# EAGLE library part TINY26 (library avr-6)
Atmel Tiny26/261/461/861

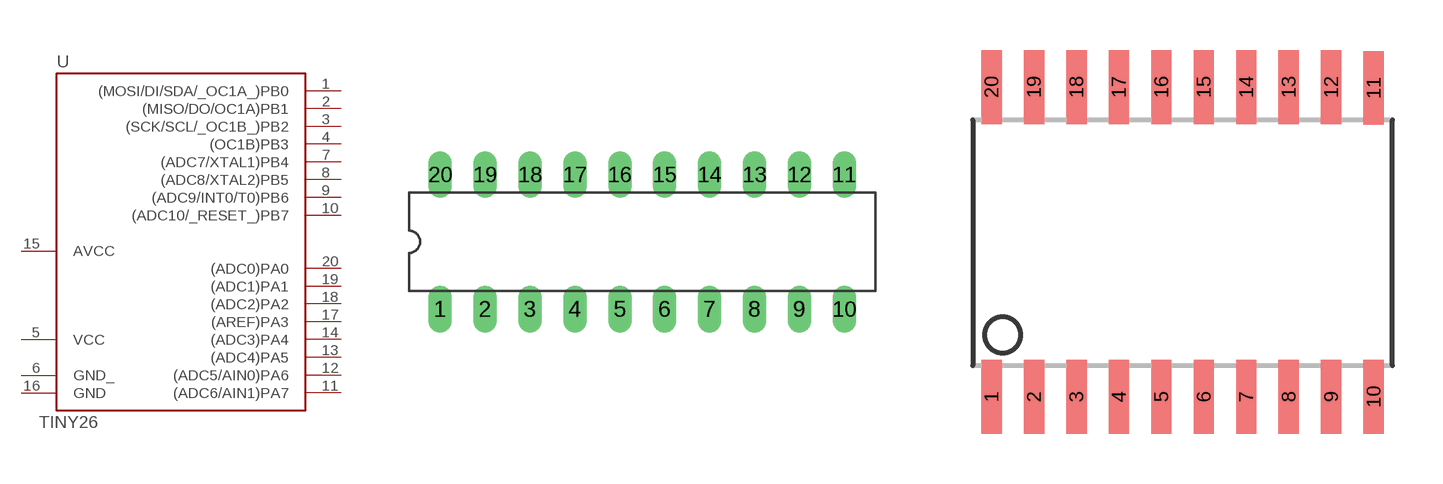
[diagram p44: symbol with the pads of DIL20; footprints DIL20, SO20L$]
Designator prefix -

## TINY26P  [DIL20]
1  (MOSI/DI/SDA/_OC1A_)PB0
2  (MISO/DO/OC1A)PB1
3  (SCK/SCL/_OC1B_)PB2
4  (OC1B)PB3
5  VCC  pwr
6  GND_  pwr
7  (ADC7/XTAL1)PB4
8  (ADC8/XTAL2)PB5
9  (ADC9/INT0/T0)PB6
10  (ADC10/_RESET_)PB7
11  (ADC6/AIN1)PA7
12  (ADC5/AIN0)PA6
13  (ADC4)PA5
14  (ADC3)PA4
15  AVCC  pwr
16  GND  pwr
17  (AREF)PA3
18  (ADC2)PA2
19  (ADC1)PA1
20  (ADC0)PA0

## TINY26S  [SO20L$]
Pads as for DIL20

## TINY26M  [MLF32]
2  (OC1B)PB3
4  VCC  pwr
5  GND_  pwr
7  (ADC7/XTAL1)PB4
8  (ADC8/XTAL2)PB5
10  (ADC9/INT0/T0)PB6
11  (ADC10/_RESET_)PB7
13  (ADC6/AIN1)PA7
14  (ADC5/AIN0)PA6
15  (ADC4)PA5
17  (ADC3)PA4
18  AVCC  pwr
21  GND  pwr
22  (AREF)PA3
23  (ADC2)PA2
25  (ADC1)PA1
26  (ADC0)PA0
30  (MOSI/DI/SDA/_OC1A_)PB0
31  (MISO/DO/OC1A)PB1
32  (SCK/SCL/_OC1B_)PB2

## Footprint DIL20 (pad centres in mm)
Dual In Line
drill 0.813 long: 1 -11.43,-3.81; 2 -8.89,-3.81; 3 -6.35,-3.81; 4 -3.81,-3.81; 5 -1.27,-3.81; 6 1.27,-3.81; 7 3.81,-3.81; 8 6.35,-3.81; 9 8.89,-3.81; 10 11.43,-3.81; 11 11.43,3.81; 12 8.89,3.81; 13 6.35,3.81; 14 3.81,3.81; 15 1.27,3.81; 16 -1.27,3.81; 17 -3.81,3.81; 18 -6.35,3.81; 19 -8.89,3.81; 20 -11.43,3.81

## Footprint SO20L$ (pad centres in mm)
Small Outline Package, large
smd 0.61 x 2.21: 1 -5.715,-4.636; 2 -4.445,-4.636; 3 -3.175,-4.636; 4 -1.905,-4.636; 5 -0.635,-4.636; 6 0.635,-4.636; 7 1.905,-4.636; 8 3.175,-4.636; 9 4.445,-4.636; 10 5.715,-4.636; 11 5.715,4.61; 12 4.445,4.636; 13 3.175,4.636; 14 1.905,4.636; 15 0.635,4.636; 16 -0.635,4.636; 17 -1.905,4.636; 18 -3.175,4.636; 19 -4.445,4.636; 20 -5.715,4.636

## Footprint MLF32 (pad centres in mm)
32M1-A Micro Lead Frame package (MLF)
smd 0.7 x 0.3: 1 -2.35,1.75; 2 -2.35,1.25; 3 -2.35,0.75; 4 -2.35,0.25; 5 -2.35,-0.25; 6 -2.35,-0.75; 7 -2.35,-1.25; 8 -2.35,-1.75; 17 2.35,-1.75; 18 2.35,-1.25; 19 2.35,-0.75; 20 2.35,-0.25; 21 2.35,0.25; 22 2.35,0.75; 23 2.35,1.25; 24 2.35,1.75
smd 0.3 x 0.7: 9 -1.75,-2.35; 10 -1.25,-2.35; 11 -0.75,-2.35; 12 -0.25,-2.35; 13 0.25,-2.35; 14 0.75,-2.35; 15 1.25,-2.35; 16 1.75,-2.35; 25 1.75,2.35; 26 1.25,2.35; 27 0.75,2.35; 28 0.25,2.35; 29 -0.25,2.35; 30 -0.75,2.35; 31 -1.25,2.35; 32 -1.75,2.35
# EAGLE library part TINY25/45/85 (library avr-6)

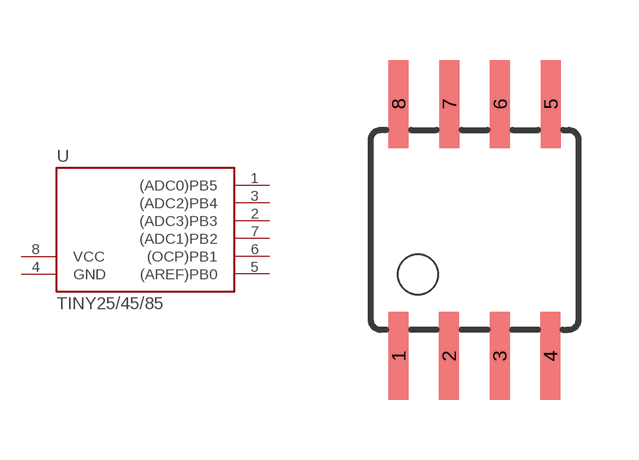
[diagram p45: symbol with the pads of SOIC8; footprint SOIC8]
Designator prefix -

## TINY25/45/85-20SU  [SOIC8]
1  (ADC0)PB5
2  (ADC3)PB3
3  (ADC2)PB4
4  GND  pwr
5  (AREF)PB0
6  (OCP)PB1
7  (ADC1)PB2
8  VCC  pwr

## Footprint SOIC8 (pad centres in mm)
Wide Plastic Gull Wing Small Outline Package
smd 0.5 x 2.2: 1 -1.905,-3.154; 2 -0.645,-3.154; 3 0.625,-3.154; 4 1.895,-3.154; 5 1.905,3.154; 6 0.635,3.154; 7 -0.635,3.154; 8 -1.905,3.154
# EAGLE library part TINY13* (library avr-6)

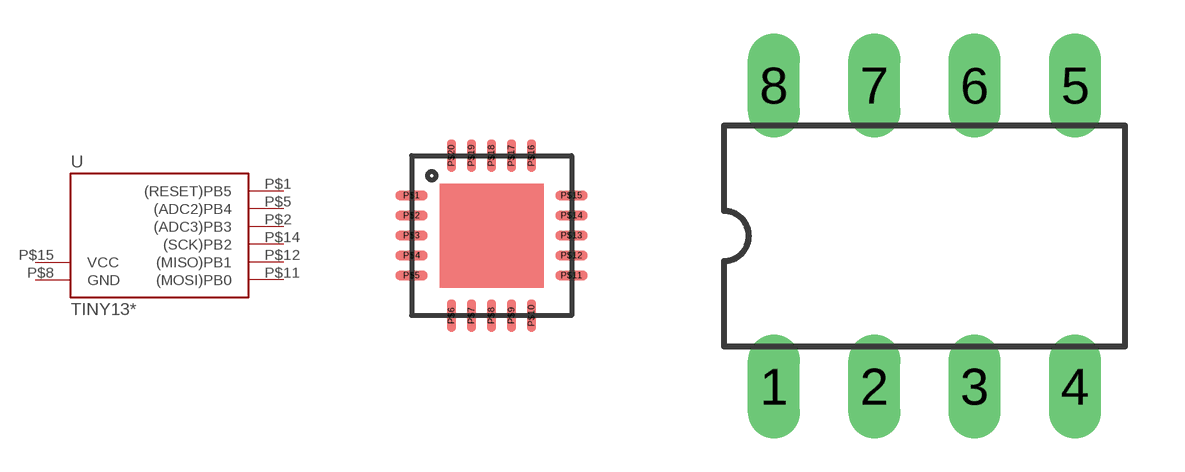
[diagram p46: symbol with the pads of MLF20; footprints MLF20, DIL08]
Designator prefix -

## TINY1320M1  [MLF20]
P$1  (RESET)PB5
P$2  (ADC3)PB3
P$5  (ADC2)PB4
P$8  GND  pwr
P$11  (MOSI)PB0
P$12  (MISO)PB1
P$14  (SCK)PB2
P$15  VCC  pwr

## TINY138P3  [DIL08]
1  (RESET)PB5
2  (ADC3)PB3
3  (ADC2)PB4
4  GND  pwr
5  (MOSI)PB0
6  (MISO)PB1
7  (SCK)PB2
8  VCC  pwr

## TINY138S2  [SO08]
Pads as for DIL08

## TINY13S8S1  [SO08-GW]
Pads as for DIL08

## Footprint MLF20 (pad centres in mm)
HP-VFQFP-N20 Micro Lead Frame package (MLF)
smd 0.8 x 0.23: P$1 -2,1; P$2 -2,0.5; P$3 -2,0; P$4 -2,-0.5; P$5 -2,-1; P$11 2,-1; P$12 2,-0.5; P$13 2,0; P$14 2,0.5; P$15 2,1
smd 0.23 x 0.8: P$6 -1,-2; P$7 -0.5,-2; P$8 0,-2; P$9 0.5,-2; P$10 1,-2; P$16 1,2; P$17 0.5,2; P$18 0,2; P$19 -0.5,2; P$20 -1,2

## Footprint DIL08 (pad centres in mm)
Dual In Line
drill 0.813 long: 1 -3.81,-3.81; 2 -1.27,-3.81; 3 1.27,-3.81; 4 3.81,-3.81; 5 3.81,3.81; 6 1.27,3.81; 7 -1.27,3.81; 8 -3.81,3.81

## Footprint SO08 (pad centres in mm)
Small Outline Package
smd 0.61 x 2.21: 1 -1.905,-2.616; 2 -0.635,-2.616; 3 0.635,-2.616; 4 1.905,-2.616; 5 1.905,2.616; 6 0.635,2.616; 7 -0.635,2.616; 8 -1.905,2.616

## Footprint SO08-GW (pad centres in mm)
Small Outline Package, gull wing
smd 0.762 x 2.21: 1 -3.81,-4.318; 2 -1.27,-4.318; 3 1.27,-4.318; 4 3.81,-4.318; 5 3.81,4.318; 6 1.27,4.318; 7 -1.27,4.318; 8 -3.81,4.318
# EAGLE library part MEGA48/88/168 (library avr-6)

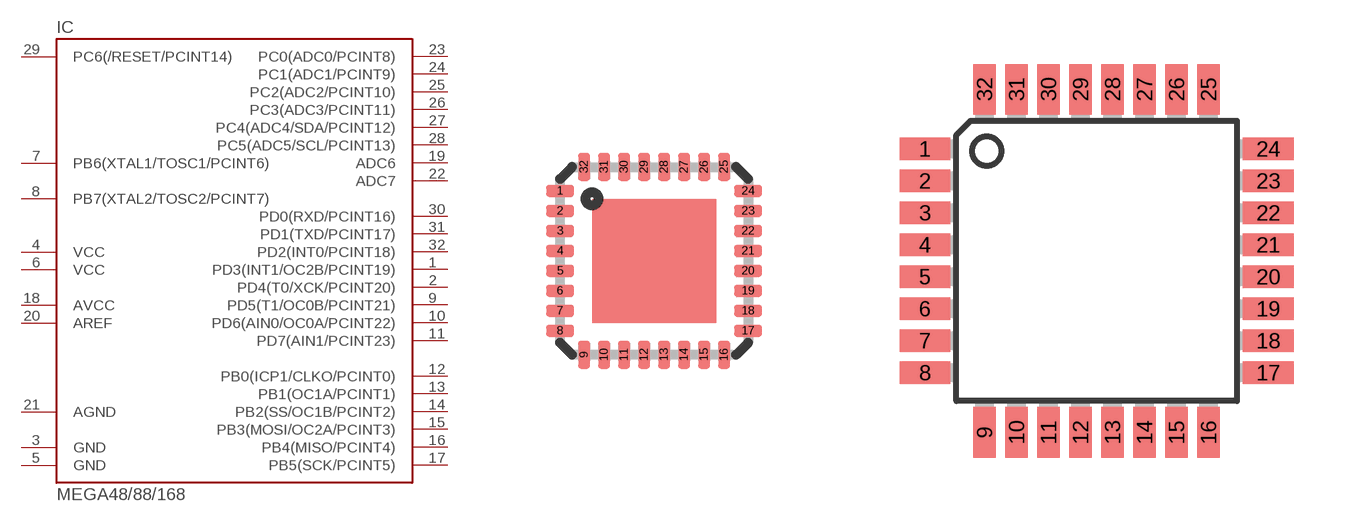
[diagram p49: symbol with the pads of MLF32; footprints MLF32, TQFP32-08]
Designator prefix IC

## MEGA48/88/168-MU  [MLF32]
1  PD3(INT1/OC2B/PCINT19)
2  PD4(T0/XCK/PCINT20)
3  GND  pwr
4  VCC  pwr
5  GND  pwr
6  VCC  pwr
7  PB6(XTAL1/TOSC1/PCINT6)
8  PB7(XTAL2/TOSC2/PCINT7)
9  PD5(T1/OC0B/PCINT21)
10  PD6(AIN0/OC0A/PCINT22)
11  PD7(AIN1/PCINT23)
12  PB0(ICP1/CLKO/PCINT0)
13  PB1(OC1A/PCINT1)
14  PB2(SS/OC1B/PCINT2)
15  PB3(MOSI/OC2A/PCINT3)
16  PB4(MISO/PCINT4)
17  PB5(SCK/PCINT5)
18  AVCC  pas
19  ADC6  pas
20  AREF  pas
21  AGND  pwr
22  ADC7  pas
23  PC0(ADC0/PCINT8)
24  PC1(ADC1/PCINT9)
25  PC2(ADC2/PCINT10)
26  PC3(ADC3/PCINT11)
27  PC4(ADC4/SDA/PCINT12)
28  PC5(ADC5/SCL/PCINT13)
29  PC6(/RESET/PCINT14)
30  PD0(RXD/PCINT16)
31  PD1(TXD/PCINT17)
32  PD2(INT0/PCINT18)

## MEGA48/88/168-AU  [TQFP32-08]
Pads as for MLF32

## Footprint MLF32 (pad centres in mm)
32M1-A Micro Lead Frame package (MLF)
smd 0.7 x 0.3: 1 -2.35,1.75; 2 -2.35,1.25; 3 -2.35,0.75; 4 -2.35,0.25; 5 -2.35,-0.25; 6 -2.35,-0.75; 7 -2.35,-1.25; 8 -2.35,-1.75; 17 2.35,-1.75; 18 2.35,-1.25; 19 2.35,-0.75; 20 2.35,-0.25; 21 2.35,0.25; 22 2.35,0.75; 23 2.35,1.25; 24 2.35,1.75
smd 0.3 x 0.7: 9 -1.75,-2.35; 10 -1.25,-2.35; 11 -0.75,-2.35; 12 -0.25,-2.35; 13 0.25,-2.35; 14 0.75,-2.35; 15 1.25,-2.35; 16 1.75,-2.35; 25 1.75,2.35; 26 1.25,2.35; 27 0.75,2.35; 28 0.25,2.35; 29 -0.25,2.35; 30 -0.75,2.35; 31 -1.25,2.35; 32 -1.75,2.35

## Footprint TQFP32-08 (pad centres in mm)
Thin Plasic Quad Flat Package Grid 0.8 mm
smd 1.27 x 0.559: 1 -4.293,2.8; 2 -4.293,2; 3 -4.293,1.2; 4 -4.293,0.4; 5 -4.293,-0.4; 6 -4.293,-1.2; 7 -4.293,-2; 8 -4.293,-2.8; 17 4.293,-2.8; 18 4.293,-2; 19 4.293,-1.2; 20 4.293,-0.4; 21 4.293,0.4; 22 4.293,1.2; 23 4.293,2; 24 4.293,2.8
smd 0.559 x 1.27: 9 -2.8,-4.293; 10 -2,-4.293; 11 -1.2,-4.293; 12 -0.4,-4.293; 13 0.4,-4.293; 14 1.2,-4.293; 15 2,-4.293; 16 2.8,-4.293; 25 2.8,4.293; 26 2,4.293; 27 1.2,4.293; 28 0.4,4.293; 29 -0.4,4.293; 30 -1.2,4.293; 31 -2,4.293; 32 -2.8,4.293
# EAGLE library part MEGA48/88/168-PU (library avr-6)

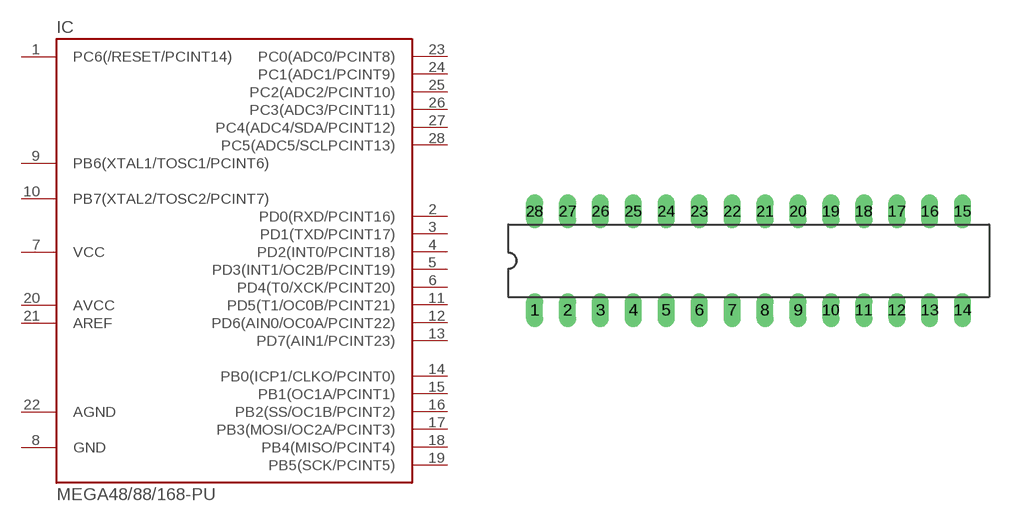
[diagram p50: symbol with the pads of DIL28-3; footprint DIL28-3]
Designator prefix IC

## MEGA48/88/168-PU  [DIL28-3]
1  PC6(/RESET/PCINT14)
2  PD0(RXD/PCINT16)
3  PD1(TXD/PCINT17)
4  PD2(INT0/PCINT18)
5  PD3(INT1/OC2B/PCINT19)
6  PD4(T0/XCK/PCINT20)
7  VCC  pwr
8  GND  pwr
9  PB6(XTAL1/TOSC1/PCINT6)
10  PB7(XTAL2/TOSC2/PCINT7)
11  PD5(T1/OC0B/PCINT21)
12  PD6(AIN0/OC0A/PCINT22)
13  PD7(AIN1/PCINT23)
14  PB0(ICP1/CLKO/PCINT0)
15  PB1(OC1A/PCINT1)
16  PB2(SS/OC1B/PCINT2)
17  PB3(MOSI/OC2A/PCINT3)
18  PB4(MISO/PCINT4)
19  PB5(SCK/PCINT5)
20  AVCC  pas
21  AREF  pas
22  AGND  pwr
23  PC0(ADC0/PCINT8)
24  PC1(ADC1/PCINT9)
25  PC2(ADC2/PCINT10)
26  PC3(ADC3/PCINT11)
27  PC4(ADC4/SDA/PCINT12)
28  PC5(ADC5/SCLPCINT13)

## Footprint DIL28-3 (pad centres in mm)
Dual In Line 0.3 inch
drill 0.813 long: 1 -16.51,-3.81; 2 -13.97,-3.81; 3 -11.43,-3.81; 4 -8.89,-3.81; 5 -6.35,-3.81; 6 -3.81,-3.81; 7 -1.27,-3.81; 8 1.27,-3.81; 9 3.81,-3.81; 10 6.35,-3.81; 11 8.89,-3.81; 12 11.43,-3.81; 13 13.97,-3.81; 14 16.51,-3.81; 15 16.51,3.81; 16 13.97,3.81; 17 11.43,3.81; 18 8.89,3.81; 19 6.35,3.81; 20 3.81,3.81; 21 1.27,3.81; 22 -1.27,3.81; 23 -3.81,3.81; 24 -6.35,3.81; 25 -8.89,3.81; 26 -11.43,3.81; 27 -13.97,3.81; 28 -16.51,3.81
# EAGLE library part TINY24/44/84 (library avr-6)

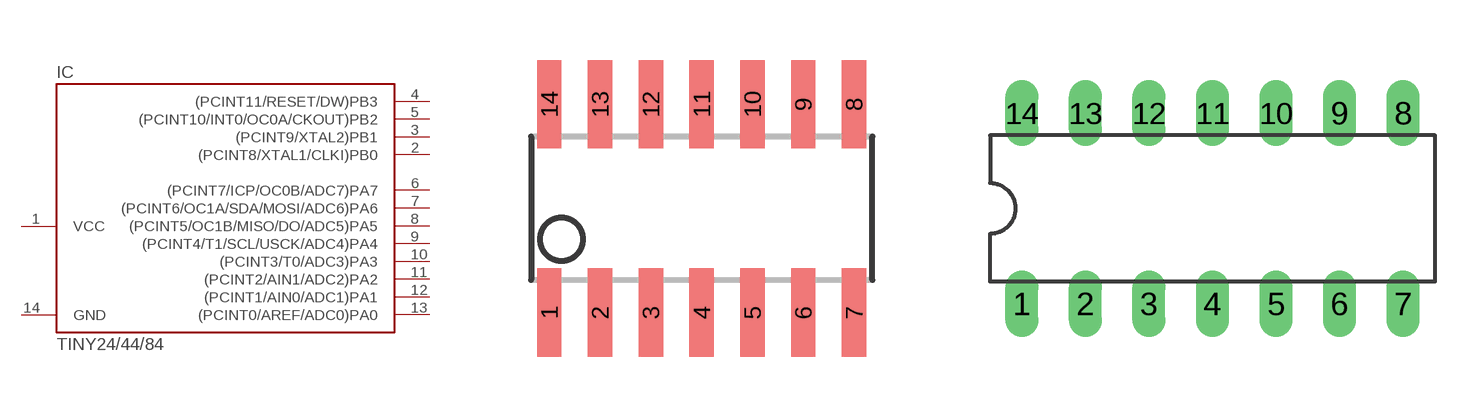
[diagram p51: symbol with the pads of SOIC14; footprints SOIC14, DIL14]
Designator prefix IC

## TINY24/44/84-SSU  [SOIC14]
1  VCC  pwr
2  (PCINT8/XTAL1/CLKI)PB0
3  (PCINT9/XTAL2)PB1
4  (PCINT11/RESET/DW)PB3
5  (PCINT10/INT0/OC0A/CKOUT)PB2
6  (PCINT7/ICP/OC0B/ADC7)PA7
7  (PCINT6/OC1A/SDA/MOSI/ADC6)PA6
8  (PCINT5/OC1B/MISO/DO/ADC5)PA5
9  (PCINT4/T1/SCL/USCK/ADC4)PA4
10  (PCINT3/T0/ADC3)PA3
11  (PCINT2/AIN1/ADC2)PA2
12  (PCINT1/AIN0/ADC1)PA1
13  (PCINT0/AREF/ADC0)PA0
14  GND  pwr

## TINY24/44/84-PU  [DIL14]
Pads as for SOIC14

## TINY24/44/84-MU  [QFN/MLF20]
1  (PCINT4/T1/SCL/USCK/ADC4)PA4
2  (PCINT3/T0/ADC3)PA3
3  (PCINT2/AIN1/ADC2)PA2
4  (PCINT1/AIN0/ADC1)PA1
5  (PCINT0/AREF/ADC0)PA0
8  GND  pwr
9  VCC  pwr
11  (PCINT8/XTAL1/CLKI)PB0
12  (PCINT9/XTAL2)PB1
13  (PCINT11/RESET/DW)PB3
14  (PCINT10/INT0/OC0A/CKOUT)PB2
15  (PCINT7/ICP/OC0B/ADC7)PA7
16  (PCINT6/OC1A/SDA/MOSI/ADC6)PA6
20  (PCINT5/OC1B/MISO/DO/ADC5)PA5

## Footprint SOIC14 (pad centres in mm)
Small Outline Package
smd 0.61 x 2.21: 1 -3.81,-2.603; 2 -2.54,-2.603; 3 -1.27,-2.603; 4 0,-2.603; 5 1.27,-2.603; 6 2.54,-2.603; 7 3.81,-2.603; 8 3.81,2.603; 9 2.54,2.603; 10 1.27,2.603; 11 0,2.603; 12 -1.27,2.603; 13 -2.54,2.603; 14 -3.81,2.603

## Footprint DIL14 (pad centres in mm)
Dual In Line Package
drill 0.813 long: 1 -7.62,-3.81; 2 -5.08,-3.81; 3 -2.54,-3.81; 4 0,-3.81; 5 2.54,-3.81; 6 5.08,-3.81; 7 7.62,-3.81; 8 7.62,3.81; 9 5.08,3.81; 10 2.54,3.81; 11 0,3.81; 12 -2.54,3.81; 13 -5.08,3.81; 14 -7.62,3.81

## Footprint QFN/MLF20 (pad centres in mm)
HP-VFQFP-N20 Micro Lead Frame package (MLF)
smd 0.9 x 0.35: 1 -2.25,1.3; 2 -2.25,0.65; 3 -2.25,0; 4 -2.25,-0.65; 5 -2.25,-1.3; 11 2.25,-1.3; 12 2.25,-0.65; 13 2.25,0; 14 2.25,0.65; 15 2.25,1.3
smd 0.35 x 0.9: 6 -1.3,-2.25; 7 -0.65,-2.25; 8 0,-2.25; 9 0.65,-2.25; 10 1.3,-2.25; 16 1.3,2.25; 17 0.65,2.25; 18 0,2.25; 19 -0.65,2.25; 20 -1.3,2.25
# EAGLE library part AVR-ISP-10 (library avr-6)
AVR ISP-10 Serial Programming Header

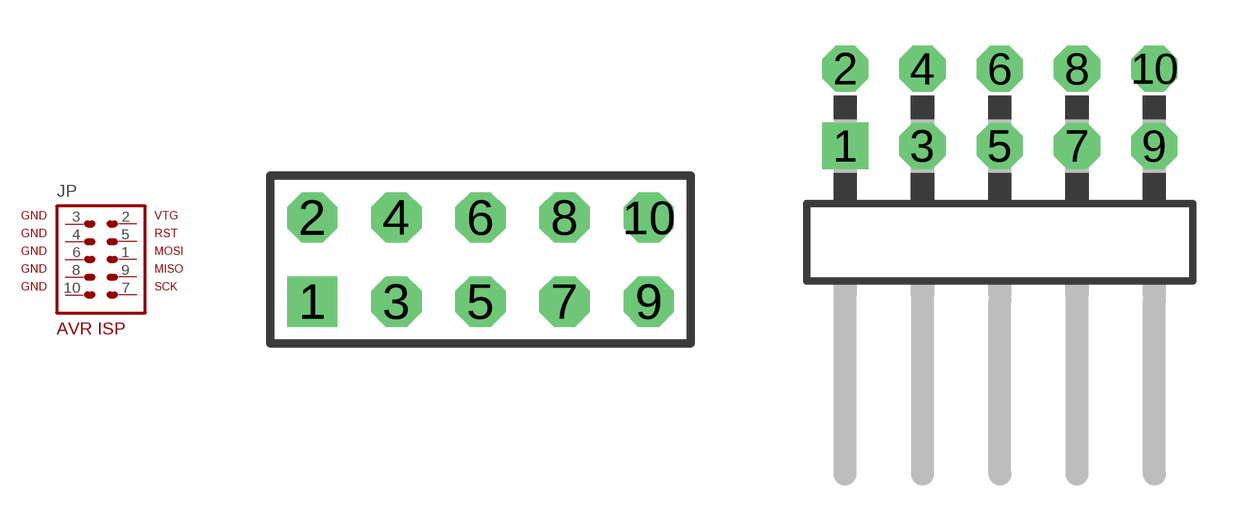
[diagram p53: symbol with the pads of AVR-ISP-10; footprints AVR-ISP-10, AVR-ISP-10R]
Designator prefix JP

## AVR-ISP-10  [AVR-ISP-10]
1  1  pas
2  2  pas
3  3  pas
4  4  pas
5  5  pas
6  6  pas
7  7  pas
8  8  pas
9  9  pas
10  10  pas

## AVR-ISP-10R  [AVR-ISP-10R]
Pads as for AVR-ISP-10

## Footprint AVR-ISP-10 (pad centres in mm)
PIN HEADER AVR ISP 10 Pin, 0.1" Straight
drill 1.016 square: 1 -5.08,-1.27
drill 1.016 octagon: 2 -5.08,1.27; 3 -2.54,-1.27; 4 -2.54,1.27; 5 0,-1.27; 6 0,1.27; 7 2.54,-1.27; 8 2.54,1.27; 9 5.08,-1.27; 10 5.08,1.27

## Footprint AVR-ISP-10R (pad centres in mm)
PIN HEADER AVR ISP 10 Pin, 0.1" Right Angle
drill 1.016 square: 1 -5.08,-1.27
drill 1.016 octagon: 2 -5.08,1.27; 3 -2.54,-1.27; 4 -2.54,1.27; 5 0,-1.27; 6 0,1.27; 7 2.54,-1.27; 8 2.54,1.27; 10 5.08,1.27
drill 1.016 pad 1.422 octagon: 9 5.08,-1.27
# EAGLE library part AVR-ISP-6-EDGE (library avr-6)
6 pin edge connector for ISP with ATMEL MCUs. Developed by Craig Moates (craig at moates dot net). Library by David Blundell (blundar at gmail dot com). Often, even a 6 pin header is really inconvenient for board layout and/or production. This SMD-only header is our de-facto standard for using an edge connector for programming with the help of a 6pin/10pin to edge card adapter.

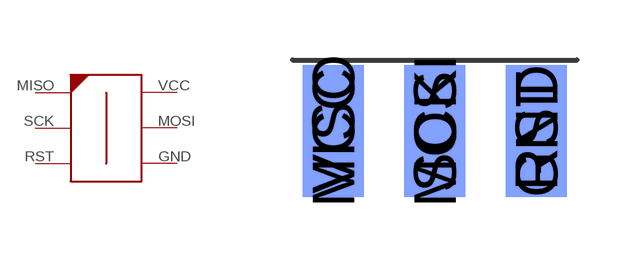
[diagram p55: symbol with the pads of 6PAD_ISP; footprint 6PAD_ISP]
Designator prefix -

## AVR-ISP-6-EDGE  [6PAD_ISP]
GND  P$4
MISO  P$1
MOSI  P$5
RST  P$3
SCK  P$2
VCC  P$6

## Footprint 6PAD_ISP (pad centres in mm)
smd 1.524 x 3.302 bottom: GND 2.54,0; MOSI 0,0; VCC -2.54,0
smd 1.524 x 3.302: MISO -2.54,0; RST 2.54,0; SCK 0,0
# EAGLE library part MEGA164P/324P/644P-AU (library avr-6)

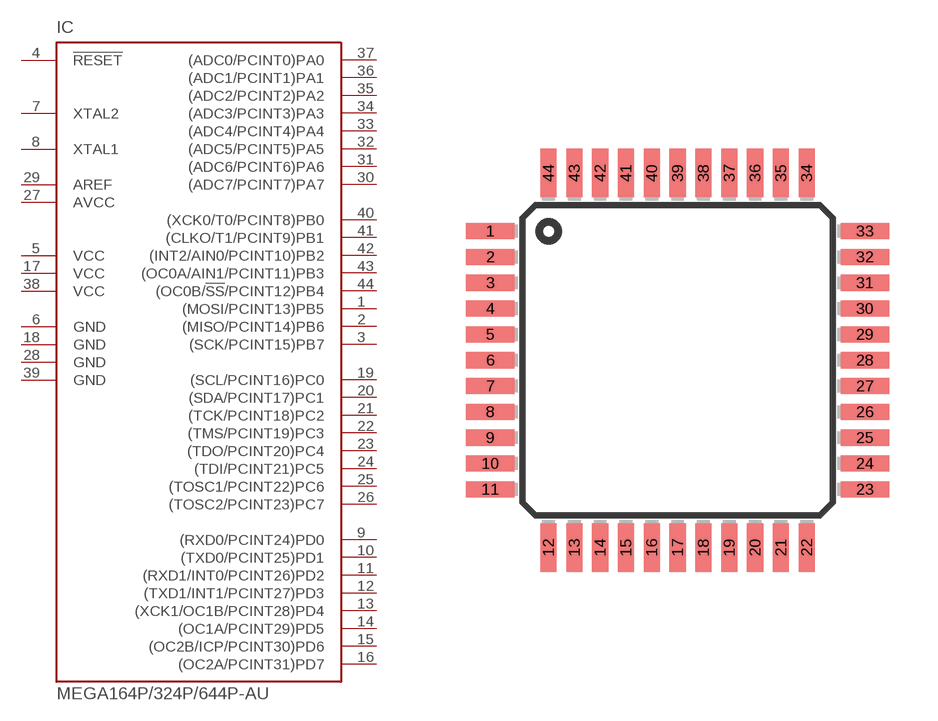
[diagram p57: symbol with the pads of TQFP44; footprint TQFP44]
Designator prefix IC

## MEGA164P/324P/644P-AU  [TQFP44]
1  (MOSI/PCINT13)PB5
2  (MISO/PCINT14)PB6
3  (SCK/PCINT15)PB7
4  !RESET  in
5  VCC  pwr
6  GND  pwr
7  XTAL2  out
8  XTAL1  in
9  (RXD0/PCINT24)PD0
10  (TXD0/PCINT25)PD1
11  (RXD1/INT0/PCINT26)PD2
12  (TXD1/INT1/PCINT27)PD3
13  (XCK1/OC1B/PCINT28)PD4
14  (OC1A/PCINT29)PD5
15  (OC2B/ICP/PCINT30)PD6
16  (OC2A/PCINT31)PD7
17  VCC  pwr
18  GND  pwr
19  (SCL/PCINT16)PC0
20  (SDA/PCINT17)PC1
21  (TCK/PCINT18)PC2
22  (TMS/PCINT19)PC3
23  (TDO/PCINT20)PC4
24  (TDI/PCINT21)PC5
25  (TOSC1/PCINT22)PC6
26  (TOSC2/PCINT23)PC7
27  AVCC  pwr
28  GND  pwr
29  AREF  pwr
30  (ADC7/PCINT7)PA7
31  (ADC6/PCINT6)PA6
32  (ADC5/PCINT5)PA5
33  (ADC4/PCINT4)PA4
34  (ADC3/PCINT3)PA3
35  (ADC2/PCINT2)PA2
36  (ADC1/PCINT1)PA1
37  (ADC0/PCINT0)PA0
38  VCC  pwr
39  GND  pwr
40  (XCK0/T0/PCINT8)PB0
41  (CLKO/T1/PCINT9)PB1
42  (INT2/AIN0/PCINT10)PB2
43  (OC0A/AIN1/PCINT11)PB3
44  (OC0B/!SS!/PCINT12)PB4

## Footprint TQFP44 (pad centres in mm)
Thin Plasic Quad Flat Package
smd 1.5 x 0.5: 1 -5.8,4; 2 -5.8,3.2; 3 -5.8,2.4; 4 -5.8,1.6; 5 -5.8,0.8; 6 -5.8,0; 7 -5.8,-0.8; 8 -5.8,-1.6; 9 -5.8,-2.4; 10 -5.8,-3.2; 11 -5.8,-4; 23 5.8,-4; 24 5.8,-3.2; 25 5.8,-2.4; 26 5.8,-1.6; 27 5.8,-0.8; 28 5.8,0; 29 5.8,0.8; 30 5.8,1.6; 31 5.8,2.4; 32 5.8,3.2; 33 5.8,4
smd 0.5 x 1.5: 12 -4,-5.8; 13 -3.2,-5.8; 14 -2.4,-5.8; 15 -1.6,-5.8; 16 -0.8,-5.8; 17 0,-5.8; 18 0.8,-5.8; 19 1.6,-5.8; 20 2.4,-5.8; 21 3.2,-5.8; 22 4,-5.8; 34 4,5.8; 35 3.2,5.8; 36 2.4,5.8; 37 1.6,5.8; 38 0.8,5.8; 39 0,5.8; 40 -0.8,5.8; 41 -1.6,5.8; 42 -2.4,5.8; 43 -3.2,5.8; 44 -4,5.8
